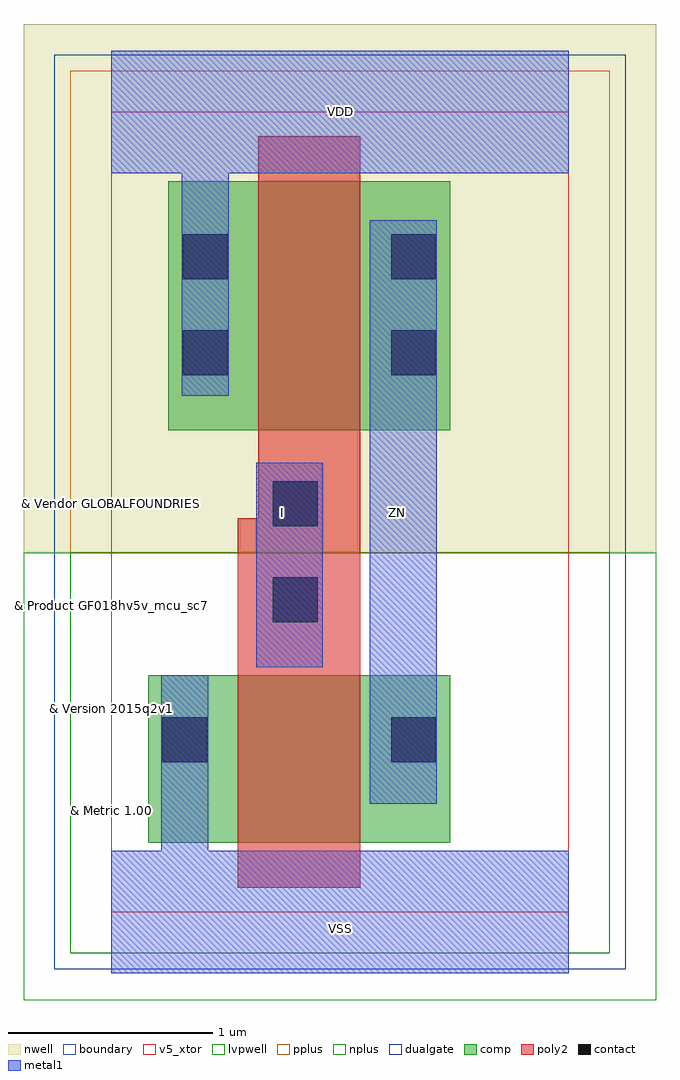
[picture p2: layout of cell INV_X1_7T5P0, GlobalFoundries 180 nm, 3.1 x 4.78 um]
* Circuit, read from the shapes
.subckt INV_X1_7T5P0 I VDD VSS ZN
XM1 ZN I VSS VSUBS nfet_05v0 w=0.82u l=0.6u
XM2 ZN I VDD n1 pfet_05v0 w=1.22u l=0.5u
.ends

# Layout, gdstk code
import gdstk
lib = gdstk.Library(unit=1e-6, precision=1e-09)
def R(c, l, rs):  # rectangles x0, y0, x1, y1
    for r in rs: c.add(gdstk.rectangle(r[:2], r[2:], *l))
def P(c, l, *ps):  # polygons
    for p in ps: c.add(gdstk.Polygon(p, *l))
boundary = (0, 0)
nwell = (21, 0)
comp = (22, 0)
poly2 = (30, 0)
pplus = (31, 0)
nplus = (32, 0)
contact = (33, 0)
metal1 = (34, 0)
dualgate = (55, 0)
v5_xtor = (112, 1)
lvpwell = (204, 0)

inv_x1_7t5p0 = lib.new_cell('INV_X1_7T5P0')
R(inv_x1_7t5p0, boundary, [(0,0,2.24,3.92)])
R(inv_x1_7t5p0, nwell, [(-0.43,1.76,2.67,4.35)])
R(inv_x1_7t5p0, comp, [(0.18,0.34,1.66,1.16), (0.28,2.36,1.66,3.58)])
P(inv_x1_7t5p0, poly2, [(0.62,0.12),(1.22,0.12),(1.22,3.8),(0.72,3.8),(0.72,1.93),(0.62,1.93)])
R(inv_x1_7t5p0, pplus, [(-0.2,1.76,2.44,4.12)])
R(inv_x1_7t5p0, nplus, [(-0.2,-0.2,2.44,1.76)])
R(inv_x1_7t5p0, contact, [(0.25,0.735,0.47,0.955), (1.37,0.735,1.59,0.955), (0.79,1.42,1.01,1.64), (0.79,1.89,1.01,2.11), (0.35,2.63,0.57,2.85), (1.37,2.63,1.59,2.85), (0.35,3.1,0.57,3.32), (1.37,3.1,1.59,3.32)])
R(inv_x1_7t5p0, metal1, [(1.265,0.53,1.595,3.39), (0.71,1.2,1.035,2.2)])
P(inv_x1_7t5p0, metal1, [(0,-0.3),(2.24,-0.3),(2.24,0.3),(0.475,0.3),(0.475,1.16),(0.245,1.16),(0.245,0.3),(0,0.3)],
  [(0,3.62),(0.345,3.62),(0.345,2.53),(0.575,2.53),(0.575,3.62),(2.24,3.62),(2.24,4.22),(0,4.22)])
R(inv_x1_7t5p0, dualgate, [(-0.28,-0.28,2.52,4.2)])
R(inv_x1_7t5p0, v5_xtor, [(0,0,2.24,3.92)])
R(inv_x1_7t5p0, lvpwell, [(-0.43,-0.43,2.67,1.76)])
inv_x1_7t5p0.add(gdstk.Label('VSS', (1.12,-0.08), layer=34, texttype=10))
inv_x1_7t5p0.add(gdstk.Label('ZN', (1.4,1.96), layer=34, texttype=10))
inv_x1_7t5p0.add(gdstk.Label('I', (0.84,1.96), layer=34, texttype=10))
inv_x1_7t5p0.add(gdstk.Label('VDD', (1.12,3.92), layer=34, texttype=10))
inv_x1_7t5p0.add(gdstk.Label('& Vendor GLOBALFOUNDRIES', (0,2), layer=63, texttype=63))
inv_x1_7t5p0.add(gdstk.Label('& Product GF018hv5v_mcu_sc7', (0,1.5), layer=63, texttype=63))
inv_x1_7t5p0.add(gdstk.Label('& Version 2015q2v1', (0,1), layer=63, texttype=63))
inv_x1_7t5p0.add(gdstk.Label('& Metric 1.00', (0,0.5), layer=63, texttype=63))

lib.write_gds('INV_X1_7T5P0.gds')
